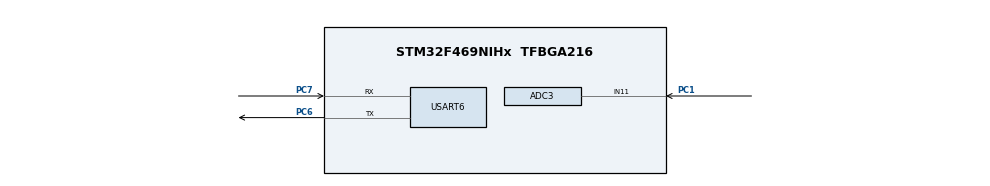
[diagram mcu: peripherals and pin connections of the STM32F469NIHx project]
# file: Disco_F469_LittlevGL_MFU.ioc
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ADC3.Channel-1\#ChannelRegularConversion=ADC_CHANNEL_11
ADC3.ClockPrescaler=ADC_CLOCK_SYNC_PCLK_DIV4
ADC3.ContinuousConvMode=DISABLE
ADC3.DiscontinuousConvMode=DISABLE
ADC3.EOCSelection=ADC_EOC_SINGLE_CONV
ADC3.ExternalTrigConv=ADC_EXTERNALTRIGCONV_T2_CC2
ADC3.ExternalTrigConvEdge=ADC_EXTERNALTRIGCONVEDGE_RISINGFALLING
ADC3.NbrOfConversion=1
ADC3.NbrOfConversionFlag=1
ADC3.Rank-1\#ChannelRegularConversion=1
ADC3.Resolution=ADC_RESOLUTION_12B
ADC3.SamplingTime-1\#ChannelRegularConversion=ADC_SAMPLETIME_144CYCLES
ADC3.ScanConvMode=DISABLE
Dma.ADC3.0.Direction=DMA_PERIPH_TO_MEMORY
Dma.ADC3.0.FIFOMode=DMA_FIFOMODE_DISABLE
Dma.ADC3.0.Instance=DMA2_Stream0
Dma.ADC3.0.MemDataAlignment=DMA_MDATAALIGN_HALFWORD
Dma.ADC3.0.MemInc=DMA_MINC_ENABLE
Dma.ADC3.0.Mode=DMA_CIRCULAR
Dma.ADC3.0.PeriphDataAlignment=DMA_PDATAALIGN_HALFWORD
Dma.ADC3.0.PeriphInc=DMA_PINC_DISABLE
Dma.ADC3.0.Priority=DMA_PRIORITY_LOW
Dma.Request0=ADC3
FATFS._MAX_SS=4096
FATFS._USE_FIND=1
Mcu.Family=STM32F4
Mcu.Name=STM32F469NIHx
Mcu.Package=TFBGA216
NVIC.DMA2_Stream0_IRQn=true\:0\:0\:false\:false\:true\:false\:true
NVIC.PriorityGroup=NVIC_PRIORITYGROUP_4
NVIC.USART6_IRQn=true\:0\:0\:false\:false\:true\:true\:true
PA13.Mode=Trace_Asynchronous_SW
PA13.Signal=SYS_JTMS-SWDIO
PA14.Mode=Trace_Asynchronous_SW
PA14.Signal=SYS_JTCK-SWCLK
PB3.Mode=Trace_Asynchronous_SW
PB3.Signal=SYS_JTDO-SWO
PC1.Signal=ADCx_IN11
PC6.Mode=Asynchronous
PC6.Signal=USART6_TX
PC7.Mode=Asynchronous
PC7.Signal=USART6_RX
PH0/OSC_IN.Mode=HSE-External-Oscillator
PH0/OSC_IN.Signal=RCC_OSC_IN
PH1/OSC_OUT.Mode=HSE-External-Oscillator
PH1/OSC_OUT.Signal=RCC_OSC_OUT
ProjectManager.HeapSize=0x2200
ProjectManager.StackSize=0x2400
ProjectManager.TargetToolchain=STM32CubeIDE
RCC.AHBFreq_Value=180000000
RCC.APB1CLKDivider=RCC_HCLK_DIV4
RCC.APB1Freq_Value=45000000
RCC.APB1TimFreq_Value=90000000
RCC.APB2CLKDivider=RCC_HCLK_DIV2
RCC.APB2Freq_Value=90000000
RCC.APB2TimFreq_Value=180000000
RCC.CortexFreq_Value=180000000
RCC.HCLKFreq_Value=180000000
RCC.HSE_VALUE=8000000
RCC.PLLM=4
RCC.PLLN=180
RCC.PLLQ=8
RCC.PLLSourceVirtual=RCC_PLLSOURCE_HSE
RCC.SYSCLKFreq_VALUE=180000000
RCC.SYSCLKSource=RCC_SYSCLKSOURCE_PLLCLK
RCC.USBFreq_Value=45000000
RCC.VCOOutputFreq_Value=360000000
SH.ADCx_IN11.0=ADC3_IN11,IN11
TIM2.Channel-Output\ Compare2\ No\ Output=TIM_CHANNEL_2
TIM2.OCMode_2=TIM_OCMODE_TOGGLE
TIM2.Period=8999
USART6.VirtualMode=VM_ASYNC
VP_CRC_VS_CRC.Mode=CRC_Activate
VP_FATFS_VS_Generic.Mode=User_defined
VP_RNG_VS_RNG.Mode=RNG_Activate
VP_TIM2_VS_ClockSourceINT.Mode=Internal
VP_TIM2_VS_no_output2.Mode=Output Compare2 No Output
board=STM32F469I-DISCO

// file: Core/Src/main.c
/* USER CODE BEGIN Header */
/**
  ******************************************************************************
  * @file           : main.c
  * @brief          : Main program body
  ******************************************************************************
  * @attention
  *
  * <h2><center>&copy; Copyright (c) 2020 STMicroelectronics.
  * All rights reserved.</center></h2>
  *
  * This software component is licensed by ST under BSD 3-Clause license,
  * the "License"; You may not use this file except in compliance with the
  * License. You may obtain a copy of the License at:
  *                        opensource.org/licenses/BSD-3-Clause
  *
  ******************************************************************************
  */
/* USER CODE END Header */

#include "main.h"
#include "adc.h"
#include "crc.h"
#include "dma.h"
#include "fatfs.h"
#include "rng.h"
#include "tim.h"
#include "usart.h"
//#include "gpio.h"

void SystemClock_Config(void);

int main(void)
{

  /* MCU Configuration--------------------------------------------------------*/

  /* Reset of all peripherals, Initializes the Flash interface and the Systick. */
  HAL_Init();

  /* Configure the system clock */
  SystemClock_Config();

  /* Initialize all configured peripherals */
//  MX_GPIO_Init();
  MX_DMA_Init();
  MX_ADC3_Init();
  MX_TIM2_Init();
  MX_CRC_Init();
  MX_RNG_Init();
  MX_USART6_UART_Init();
  MX_FATFS_Init();
  /* USER CODE BEGIN 2 */

  /*##-2- Register the file system object to the FatFs module ##############*/

#if DATA_ANALYZER
  adc_start();
#endif

  k_BspInit();

  lv_init();
  lv_port_disp_init();

  /* If calibration is not yet done, proceed with calibration */
  static uint32_t ts_status  = TS_OK;
   if (TouchScreen_IsCalibrationDone() == 0)
   {
 	  ts_status = Touchscreen_Calibration();
 	  if(ts_status == TS_OK)
 	  {
 		  BSP_LCD_Clear(LCD_COLOR_WHITE);
 		  BSP_LCD_SetTextColor(LCD_COLOR_BLUE);
 		  BSP_LCD_DisplayStringAt(0, BSP_LCD_GetYSize() - 65, (uint8_t*)"Touchscreen calibration success.", CENTER_MODE);
 	  }
   } /* of if (TouchScreen_IsCalibrationDone() == 0) */

   lv_port_indev_init();
   lv_port_fs_init();

   title_start();

   uint32_t poll_lv = HAL_GetTick();
   uint32_t poll_leds = HAL_GetTick();

   /*-------LV example-------------------------------------------------------------------------*/

   /*------------------------------------------------------------------------------------------*/

  /* USER CODE END 2 */

  /* Infinite loop */
  /* USER CODE BEGIN WHILE */
  while (1)
  {
	  if (HAL_GetTick() - poll_lv > 5){
		  poll_lv = HAL_GetTick();
		  lv_task_handler();
	  }

	  if (HAL_GetTick() - poll_leds > 20){
		  poll_leds = HAL_GetTick();
//		  BSP_LED_Toggle(LED_ORANGE);
//		  BSP_LED_Toggle(LED_GREEN);
		  BSP_LED_Toggle(LED_BLUE);
	  }

    /* USER CODE END WHILE */

  }
}

//void SystemClock_Config(void)
//{
//  RCC_OscInitTypeDef RCC_OscInitStruct = {0};
//  RCC_ClkInitTypeDef RCC_ClkInitStruct = {0};
//
//  /** Configure the main internal regulator output voltage
//  */
//  __HAL_RCC_PWR_CLK_ENABLE();
//  __HAL_PWR_VOLTAGESCALING_CONFIG(PWR_REGULATOR_VOLTAGE_SCALE1);
//  /** Initializes the CPU, AHB and APB busses clocks
//  */
//  RCC_OscInitStruct.OscillatorType = RCC_OSCILLATORTYPE_HSE;
//  RCC_OscInitStruct.HSEState = RCC_HSE_ON;
//  RCC_OscInitStruct.PLL.PLLState = RCC_PLL_ON;
//  RCC_OscInitStruct.PLL.PLLSource = RCC_PLLSOURCE_HSE;
//  RCC_OscInitStruct.PLL.PLLM = 4;
//  RCC_OscInitStruct.PLL.PLLN = 180;
//  RCC_OscInitStruct.PLL.PLLP = RCC_PLLP_DIV2;
//  RCC_OscInitStruct.PLL.PLLQ = 8;
//  RCC_OscInitStruct.PLL.PLLR = 2;
//  if (HAL_RCC_OscConfig(&RCC_OscInitStruct) != HAL_OK)
//  {
//    Error_Handler();
//  }
//  /** Activate the Over-Drive mode
//  */
//  if (HAL_PWREx_EnableOverDrive() != HAL_OK)
//  {
//    Error_Handler();
//  }
//  /** Initializes the CPU, AHB and APB busses clocks
//  */
//  RCC_ClkInitStruct.ClockType = RCC_CLOCKTYPE_HCLK|RCC_CLOCKTYPE_SYSCLK
//                              |RCC_CLOCKTYPE_PCLK1|RCC_CLOCKTYPE_PCLK2;
//  RCC_ClkInitStruct.SYSCLKSource = RCC_SYSCLKSOURCE_PLLCLK;
//  RCC_ClkInitStruct.AHBCLKDivider = RCC_SYSCLK_DIV1;
//  RCC_ClkInitStruct.APB1CLKDivider = RCC_HCLK_DIV4;
//  RCC_ClkInitStruct.APB2CLKDivider = RCC_HCLK_DIV2;
//
//  if (HAL_RCC_ClockConfig(&RCC_ClkInitStruct, FLASH_LATENCY_5) != HAL_OK)
//  {
//    Error_Handler();
//  }
//}

/* USER CODE BEGIN 4 */
void SystemClock_Config(void)
{
  RCC_ClkInitTypeDef RCC_ClkInitStruct;
  RCC_OscInitTypeDef RCC_OscInitStruct;
  HAL_StatusTypeDef ret = HAL_OK;

  /* Enable Power Control clock */
  __HAL_RCC_PWR_CLK_ENABLE();

  /* The voltage scaling allows optimizing the power consumption when the device is
     clocked below the maximum system frequency, to update the voltage scaling value
     regarding system frequency refer to product datasheet.  */
  __HAL_PWR_VOLTAGESCALING_CONFIG(PWR_REGULATOR_VOLTAGE_SCALE1);

  /* Enable HSE Oscillator and activate PLL with HSE as source */
  RCC_OscInitStruct.OscillatorType = RCC_OSCILLATORTYPE_HSE;
  RCC_OscInitStruct.HSEState = RCC_HSE_ON;
  RCC_OscInitStruct.PLL.PLLState = RCC_PLL_ON;
  RCC_OscInitStruct.PLL.PLLSource = RCC_PLLSOURCE_HSE;
#if defined(USE_STM32469I_DISCO_REVA)
  RCC_OscInitStruct.PLL.PLLM = 25;
#else
  RCC_OscInitStruct.PLL.PLLM = 8;
#endif /* USE_STM32469I_DISCO_REVA */
  RCC_OscInitStruct.PLL.PLLN = 360;
  RCC_OscInitStruct.PLL.PLLP = RCC_PLLP_DIV2;
  RCC_OscInitStruct.PLL.PLLQ = 7;
  RCC_OscInitStruct.PLL.PLLR = 6;

  ret = HAL_RCC_OscConfig(&RCC_OscInitStruct);
  if(ret != HAL_OK)
  {
    while(1) { ; }
  }

  /* Activate the OverDrive to reach the 180 MHz Frequency */
  ret = HAL_PWREx_EnableOverDrive();
  if(ret != HAL_OK)
  {
    while(1) { ; }
  }

  /* Select PLL as system clock source and configure the HCLK, PCLK1 and PCLK2 clocks dividers */
  RCC_ClkInitStruct.ClockType = (RCC_CLOCKTYPE_SYSCLK | RCC_CLOCKTYPE_HCLK | RCC_CLOCKTYPE_PCLK1 | RCC_CLOCKTYPE_PCLK2);
  RCC_ClkInitStruct.SYSCLKSource = RCC_SYSCLKSOURCE_PLLCLK;
  RCC_ClkInitStruct.AHBCLKDivider = RCC_SYSCLK_DIV1;
  RCC_ClkInitStruct.APB1CLKDivider = RCC_HCLK_DIV4;
  RCC_ClkInitStruct.APB2CLKDivider = RCC_HCLK_DIV2;

  ret = HAL_RCC_ClockConfig(&RCC_ClkInitStruct, FLASH_LATENCY_5);
  if(ret != HAL_OK)
  {
    while(1) { ; }
  }
}

/* USER CODE END 4 */

void Error_Handler(void)
{
  /* USER CODE BEGIN Error_Handler_Debug */
  /* User can add his own implementation to report the HAL error return state */
  BSP_LED_On(LED_RED);
  while(1){;}
  /* USER CODE END Error_Handler_Debug */
}

/************************ (C) COPYRIGHT STMicroelectronics *****END OF FILE****/
